# Five-layer technology and a hard block whose left edge holds small metal3
# pins between obstruction strips, as memory macros have, for routing tests.
VERSION 5.8 ;
BUSBITCHARS "[]" ;
DIVIDERCHAR "/" ;

UNITS
  DATABASE MICRONS 2000 ;
END UNITS

MANUFACTURINGGRID 0.005 ;

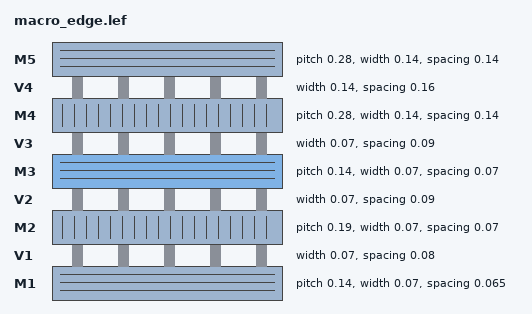
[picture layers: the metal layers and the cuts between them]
LAYER M1
  TYPE ROUTING ;
  DIRECTION HORIZONTAL ;
  PITCH 0.14 ;
  OFFSET 0.095 0.07 ;
  WIDTH 0.07 ;
  SPACING 0.065 ;
END M1

LAYER V1
  TYPE CUT ;
  WIDTH 0.07 ;
  SPACING 0.08 ;
END V1

LAYER M2
  TYPE ROUTING ;
  DIRECTION VERTICAL ;
  PITCH 0.19 ;
  OFFSET 0.095 0.07 ;
  WIDTH 0.07 ;
  SPACING 0.07 ;
END M2

LAYER V2
  TYPE CUT ;
  WIDTH 0.07 ;
  SPACING 0.09 ;
END V2

LAYER M3
  TYPE ROUTING ;
  DIRECTION HORIZONTAL ;
  PITCH 0.14 ;
  OFFSET 0.095 0.07 ;
  WIDTH 0.07 ;
  SPACING 0.07 ;
END M3

LAYER V3
  TYPE CUT ;
  WIDTH 0.07 ;
  SPACING 0.09 ;
END V3

LAYER M4
  TYPE ROUTING ;
  DIRECTION VERTICAL ;
  PITCH 0.28 ;
  OFFSET 0.095 0.07 ;
  WIDTH 0.14 ;
  SPACING 0.14 ;
END M4

LAYER V4
  TYPE CUT ;
  WIDTH 0.14 ;
  SPACING 0.16 ;
END V4

LAYER M5
  TYPE ROUTING ;
  DIRECTION HORIZONTAL ;
  PITCH 0.28 ;
  OFFSET 0.095 0.07 ;
  WIDTH 0.14 ;
  SPACING 0.14 ;
END M5

VIA M1M2 DEFAULT
  LAYER V1 ;
    RECT -0.035 -0.035 0.035 0.035 ;
  LAYER M1 ;
    RECT -0.035 -0.07 0.035 0.07 ;
  LAYER M2 ;
    RECT -0.035 -0.07 0.035 0.07 ;
END M1M2

VIA M2M3 DEFAULT
  LAYER V2 ;
    RECT -0.035 -0.035 0.035 0.035 ;
  LAYER M2 ;
    RECT -0.035 -0.07 0.035 0.07 ;
  LAYER M3 ;
    RECT -0.035 -0.07 0.035 0.07 ;
END M2M3

VIA M3M4 DEFAULT
  LAYER V3 ;
    RECT -0.035 -0.035 0.035 0.035 ;
  LAYER M3 ;
    RECT -0.07 -0.035 0.07 0.035 ;
  LAYER M4 ;
    RECT -0.07 -0.07 0.07 0.07 ;
END M3M4

VIA M4M5 DEFAULT
  LAYER V4 ;
    RECT -0.07 -0.07 0.07 0.07 ;
  LAYER M4 ;
    RECT -0.07 -0.07 0.07 0.07 ;
  LAYER M5 ;
    RECT -0.07 -0.07 0.07 0.07 ;
END M4M5

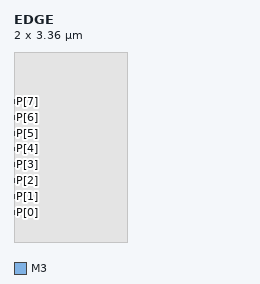
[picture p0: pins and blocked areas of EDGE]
MACRO EDGE
  CLASS BLOCK ;
  ORIGIN 0 0 ;
  SIZE 2.0 BY 3.36 ;
  PIN P[0]
    DIRECTION INPUT ;
    USE SIGNAL ;
    PORT
      LAYER M3 ;
        RECT 0 0.49 0.07 0.56 ;
    END
  END P[0]
  PIN P[1]
    DIRECTION INPUT ;
    USE SIGNAL ;
    PORT
      LAYER M3 ;
        RECT 0 0.77 0.07 0.84 ;
    END
  END P[1]
  PIN P[2]
    DIRECTION INPUT ;
    USE SIGNAL ;
    PORT
      LAYER M3 ;
        RECT 0 1.05 0.07 1.12 ;
    END
  END P[2]
  PIN P[3]
    DIRECTION INPUT ;
    USE SIGNAL ;
    PORT
      LAYER M3 ;
        RECT 0 1.33 0.07 1.4 ;
    END
  END P[3]
  PIN P[4]
    DIRECTION INPUT ;
    USE SIGNAL ;
    PORT
      LAYER M3 ;
        RECT 0 1.61 0.07 1.68 ;
    END
  END P[4]
  PIN P[5]
    DIRECTION INPUT ;
    USE SIGNAL ;
    PORT
      LAYER M3 ;
        RECT 0 1.89 0.07 1.96 ;
    END
  END P[5]
  PIN P[6]
    DIRECTION INPUT ;
    USE SIGNAL ;
    PORT
      LAYER M3 ;
        RECT 0 2.17 0.07 2.24 ;
    END
  END P[6]
  PIN P[7]
    DIRECTION INPUT ;
    USE SIGNAL ;
    PORT
      LAYER M3 ;
        RECT 0 2.45 0.07 2.52 ;
    END
  END P[7]
  OBS
    LAYER M1 ;
      RECT 0 0 2.0 3.36 ;
    LAYER M2 ;
      RECT 0 0 2.0 3.36 ;
    LAYER M3 ;
      RECT 0.07 0 2.0 3.36 ;
      RECT 0 0 0.07 0.49 ;
      RECT 0 0.56 0.07 0.77 ;
      RECT 0 0.84 0.07 1.05 ;
      RECT 0 1.12 0.07 1.33 ;
      RECT 0 1.4 0.07 1.61 ;
      RECT 0 1.68 0.07 1.89 ;
      RECT 0 1.96 0.07 2.17 ;
      RECT 0 2.24 0.07 2.45 ;
      RECT 0 2.52 0.07 3.36 ;
    LAYER M4 ;
      RECT 0 0 2.0 3.36 ;
  END
END EDGE

END LIBRARY
